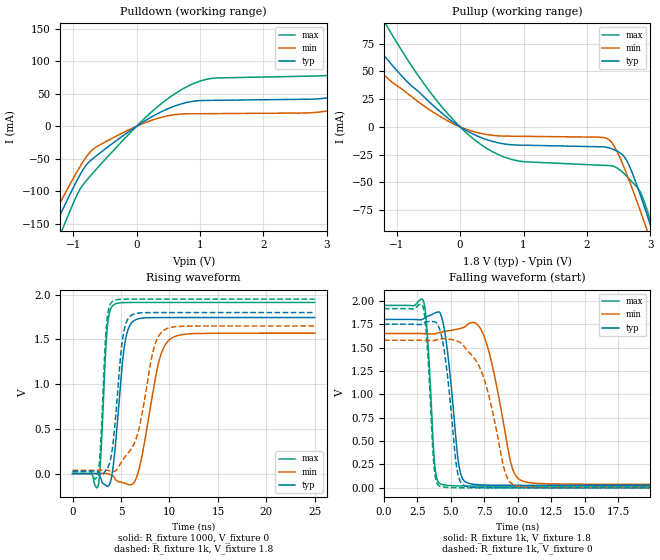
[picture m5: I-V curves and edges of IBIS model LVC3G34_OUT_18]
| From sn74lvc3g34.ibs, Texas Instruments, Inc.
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[Model]   LVC3G34_OUT_18
Model_type  Output
Vref =   0
Rref =   1000
Cref =   30p
Vmeas =   0.9
| variable   typ   min   max
C_comp   9.94pF   6.40pF   16.19pF
| C_pullup   9.16pF   6.40pF   10.36pF
| C_pulldown   10.71pF   6.76pF   16.19pF
[Temperature Range]   40   100   -40
| Ambient temperature   25   85   -40
[Voltage range]   1.8   1.65   1.95
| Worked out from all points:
|   slope of the pulldown table from 0 to 0.27 V, typ, clamps not added: 16.6 ohm
|   slope of the pullup table from 0 to 0.27 V, typ, clamps not added: 33.1 ohm
|   rising waveform, R_fixture 1000, V_fixture 0: 20-80 % time 867ps typ, 1.55ns min, 503ps max; typ from 0 V to 1.74 V
|   falling waveform, R_fixture 1k, V_fixture 1.8: 20-80 % time 716ps typ, 1.28ns min, 430ps max; typ from 1.8 V to 0.027 V
|   rising waveform, R_fixture 1k, V_fixture 1.8: 20-80 % time 873ps typ, 1.77ns min, 503ps max; typ from 0.027 V to 1.8 V
|   falling waveform, R_fixture 1k, V_fixture 0: 20-80 % time 748ps typ, 1.58ns min, 434ps max; typ from 1.75 V to 0 V
[Pulldown]
| LVC3G34_OUT_18
|   Voltage   I(typ)   I(min)   I(max)
-5V       -921.3mA   -834.5mA   -1.063A
-1.445V   -186.3mA   -162.4mA   -225.4mA
-1.25V    -145.7mA   -126mA     -178.1mA
-685mV    -49.64mA   -35.35mA   -71.84mA
610mV     31.45mA    17.97mA    50.48mA
1.215V    39.94mA    19.45mA    74.07mA
3.215V    47.58mA    27.04mA    81.89mA
3.75V     64.33mA    35.96mA    102.6mA
4.19V     79.14mA    21.53mA    128.3mA
4.615V    44.44mA    21.76mA    152.7mA
5.01V     44.71mA    21.99mA    83.17mA
10V       49.72mA    24.78mA    91.33mA
[Pullup]
| LVC3G34_OUT_18
|   Voltage   I(typ)   I(min)   I(max)
-5V       401.9mA    301.7mA    569.7mA
-1.995V   124.3mA    92.87mA    180.5mA
-1.525V   87.6mA     64.51mA    128.6mA
-1.245V   67.41mA    49.06mA    99.76mA
-215mV    8.959mA    6.079mA    13.21mA
460mV     -12.21mA   -7.201mA   -20.69mA
1.005V    -16.45mA   -8.461mA   -31.35mA
2.32V     -18.45mA   -10.52mA   -34.74mA
2.62V     -29.72mA   -41.55mA   -44.14mA
2.935V    -77.24mA   -91.1mA    -72.7mA
3.07V     -101mA     -113.7mA   -97.52mA
10V       -1.501A    -1.413A    -1.659A
[Ramp]
| LVC3G34_OUT_18
| variable   typ   min   max
dV/dt_r   1.13/9.33E-10   1.02/1.66E-09   1.24/5.46E-10
dV/dt_f   1.11/7.61E-10   1.04/1.41E-09   1.20/4.54E-10
R_load = 1k
[Rising Waveform]
| LVC3G34_OUT_18
R_fixture =   1000
C_fixture =   0
L_fixture =   0
V_fixture =   0
V_fixture_min = 0
V_fixture_max = 0
|   Time   V(typ)   V(min)   V(max)
0s        112.7pV    7.745nV    2.81nV
2.645ns   -9.907mV   1.897mV    -132.8mV
2.915ns   -53.04mV   2.167mV    194.2mV
3.555ns   -140.9mV   796.2uV    1.594V
4.24ns    126.2mV    -31.5mV    1.887V
5.33ns    1.408V     -105.5mV   1.912V
6.305ns   1.707V     -103.2mV   1.913V
8.89ns    1.744V     1.246V     1.913V
10.04ns   1.744V     1.5V       1.913V
24.99ns   1.744V     1.569V     1.913V
[Falling Waveform]
| LVC3G34_OUT_18
R_fixture =   1k
C_fixture =   0
L_fixture =   0
V_fixture =   1.8
V_fixture_min = 1.65
V_fixture_max = 1.95
|   Time   V(typ)   V(min)   V(max)
0s        1.8V       1.65V      1.95V
2.955ns   1.808V     1.648V     1.994V
3.27ns    1.834V     1.646V     1.58V
3.785ns   1.867V     1.647V     257.1mV
4.21ns    1.865V     1.663V     43.09mV
5.58ns    258.3mV    1.699V     20.91mV
6.11ns    61.74mV    1.728V     20.08mV
7.55ns    30.64mV    1.594V     19.58mV
10.17ns   27.23mV    85.41mV    19.52mV
24.99ns   26.98mV    37.55mV    19.51mV
[Rising Waveform]
| LVC3G34_OUT_18
R_fixture =   1k
C_fixture =   0
L_fixture =   0
V_fixture =   1.8
V_fixture_min = 1.65
V_fixture_max = 1.95
|   Time   V(typ)   V(min)   V(max)
0s        26.95mV    37.49mV    19.5mV
2.61ns    20.81mV    39.22mV    -6.802mV
2.89ns    -5.084mV   39.46mV    321.7mV
3.49ns    46.09mV    38.45mV    1.643V
4.125ns   295.4mV    24.99mV    1.925V
5.155ns   1.497V     147.9mV    1.949V
6.06ns    1.77V      275.6mV    1.95V
8.385ns   1.8V       1.398V     1.95V
9.44ns    1.8V       1.605V     1.95V
24.99ns   1.8V       1.65V      1.95V
[Falling Waveform]
| LVC3G34_OUT_18
R_fixture =   1k
C_fixture =   0
L_fixture =   0
V_fixture =   0
V_fixture_min = 0
V_fixture_max = 0
|   Time   V(typ)   V(min)   V(max)
0s        1.749V     1.578V     1.916V
2.93ns    1.755V     1.577V     1.928V
3.235ns   1.775V     1.575V     1.509V
3.725ns   1.776V     1.576V     251mV
4.125ns   1.71V      1.588V     21.38mV
5.435ns   217.2mV    1.571V     1.151mV
5.94ns    28.2mV     1.522V     468.6uV
7.385ns   2.007mV    1.205V     59.52uV
9.665ns   177.7uV    33.55mV    19.63uV
24.99ns   22.36uV    45.44uV    12.8uV
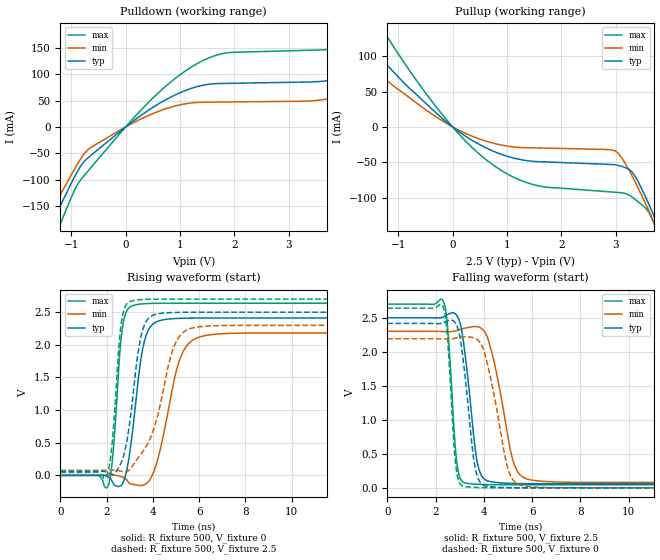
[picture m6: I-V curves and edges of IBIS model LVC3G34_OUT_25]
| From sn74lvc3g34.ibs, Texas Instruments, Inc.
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[Model]   LVC3G34_OUT_25
Model_type  Output
Vref =   0
Rref =   500
Cref =   30p
Vmeas =   1.25
| variable   typ   min   max
C_comp   9.77pF   6.16pF   14.04pF
| C_pullup   9.65pF   6.16pF   11.32pF
| C_pulldown   9.89pF   6.53pF   14.04pF
[Temperature Range]   40   100   -40
| Ambient temperature   25   85   -40
[Voltage range]   2.5   2.3   2.7
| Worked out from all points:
|   slope of the pulldown table from 0 to 0.375 V, typ, clamps not added: 13.1 ohm
|   slope of the pullup table from 0 to 0.375 V, typ, clamps not added: 19.1 ohm
|   rising waveform, R_fixture 500, V_fixture 0: 20-80 % time 503ps typ, 789ps min, 311ps max; typ from 0 V to 2.41 V
|   falling waveform, R_fixture 500, V_fixture 2.5: 20-80 % time 445ps typ, 700ps min, 284ps max; typ from 2.5 V to 0.06 V
|   rising waveform, R_fixture 500, V_fixture 2.5: 20-80 % time 533ps typ, 974ps min, 322ps max; typ from 0.06 V to 2.5 V
|   falling waveform, R_fixture 500, V_fixture 0: 20-80 % time 431ps typ, 694ps min, 272ps max; typ from 2.42 V to 0 V
[Pulldown]
| LVC3G34_OUT_25
|   Voltage   I(typ)   I(min)   I(max)
-5V       -962mA     -863.3mA   -1.124A
-1.53V    -221.1mA   -192.5mA   -267.7mA
-1.155V   -139.5mA   -119.8mA   -172mA
-665mV    -56.23mA   -40.89mA   -80.16mA
525mV     38.75mA    26.4mA     57.3mA
1.435V    79.4mA     46.8mA     126.7mA
3.83V     89.86mA    55.4mA     148.1mA
5.34V     157.5mA    105.8mA    231.8mA
5.91V     188.7mA    52.62mA    283.1mA
6.525V    93.57mA    53.13mA    299.2mA
7.5V      94.02mA    54.05mA    161.3mA
10V       98.03mA    56.54mA    166.6mA
[Pullup]
| LVC3G34_OUT_25
|   Voltage   I(typ)   I(min)   I(max)
-5V       476.9mA    373.6mA    668.8mA
-2.355V   194.1mA    148.5mA    277.6mA
-1.77V    138.1mA    104.6mA    199.1mA
-1.305V   96.51mA    72.23mA    140.3mA
-155mV    9.734mA    7.01mA     14.36mA
765mV     -34.86mA   -23.35mA   -54.93mA
1.6V      -49.31mA   -29.85mA   -83.81mA
2.995V    -53.63mA   -34.3mA    -92.61mA
3.335V    -67.41mA   -74.46mA   -101.3mA
3.72V     -128.9mA   -137.4mA   -139.3mA
3.8V      -143.3mA   -151.1mA   -154.4mA
10V       -1.404A    -1.319A    -1.567A
[Ramp]
| LVC3G34_OUT_25
| variable   typ   min   max
dV/dt_r   1.55/5.42E-10   1.40/8.48E-10   1.70/3.39E-10
dV/dt_f   1.51/4.63E-10   1.38/7.32E-10   1.64/2.95E-10
R_load = 500
[Rising Waveform]
| LVC3G34_OUT_25
R_fixture =   500
C_fixture =   0
L_fixture =   0
V_fixture =   0
V_fixture_min = 0
V_fixture_max = 0
|   Time   V(typ)   V(min)   V(max)
0s        123.5pV    5.828nV    2.514nV
2.065ns   -24.28mV   3.069mV    -156.4mV
2.265ns   -109mV     4.128mV    307.7mV
2.68ns    -128.5mV   -25.96mV   2.26V
3.18ns    866.4mV    -139.7mV   2.606V
3.515ns   1.859V     -153.7mV   2.627V
3.865ns   2.263V     -66.06mV   2.634V
5.155ns   2.406V     1.773V     2.637V
6.06ns    2.41V      2.126V     2.637V
24.99ns   2.411V     2.183V     2.637V
[Falling Waveform]
| LVC3G34_OUT_25
R_fixture =   500
C_fixture =   0
L_fixture =   0
V_fixture =   2.5
V_fixture_min = 2.3
V_fixture_max = 2.7
|   Time   V(typ)   V(min)   V(max)
0s        2.5V       2.3V       2.7V
2.32ns    2.511V     2.297V     2.745V
2.5ns     2.547V     2.295V     2.358V
2.875ns   2.536V     2.313V     383.8mV
3.21ns    1.996V     2.346V     73.62mV
3.88ns    193.9mV    2.348V     50.49mV
4.375ns   85.25mV    1.927V     46.75mV
5.22ns    65.14mV    387mV      45.35mV
5.81ns    61.99mV    127.9mV    45.17mV
24.99ns   60.11mV    78.17mV    45.05mV
[Rising Waveform]
| LVC3G34_OUT_25
R_fixture =   500
C_fixture =   0
L_fixture =   0
V_fixture =   2.5
V_fixture_min = 2.3
V_fixture_max = 2.7
|   Time   V(typ)   V(min)   V(max)
0s        60.06mV    78.1mV     45.02mV
2.015ns   48.04mV    80.46mV    17.05mV
2.235ns   13.22mV    82mV       497.6mV
2.63ns    198.6mV    64.23mV    2.328V
3.08ns    1.048V     126.6mV    2.671V
3.4ns     1.98V      289.5mV    2.69V
3.715ns   2.362V     450.8mV    2.696V
4.9ns     2.495V     1.963V     2.7V
5.675ns   2.499V     2.256V     2.7V
24.99ns   2.5V       2.3V       2.7V
[Falling Waveform]
| LVC3G34_OUT_25
R_fixture =   500
C_fixture =   0
L_fixture =   0
V_fixture =   0
V_fixture_min = 0
V_fixture_max = 0
|   Time   V(typ)   V(min)   V(max)
0s        2.416V     2.191V     2.64V
2.305ns   2.425V     2.189V     2.666V
2.485ns   2.453V     2.188V     2.238V
2.825ns   2.42V      2.2V       370.5mV
3.125ns   1.932V     2.221V     26.14mV
3.55ns    498.5mV    2.207V     8.694mV
3.78ns    123.1mV    2.161V     4.812mV
4.99ns    3.939mV    292.1mV    357.6uV
5.555ns   1.423mV    35.08mV    162.6uV
24.99ns   41.38uV    58.61uV    31.07uV
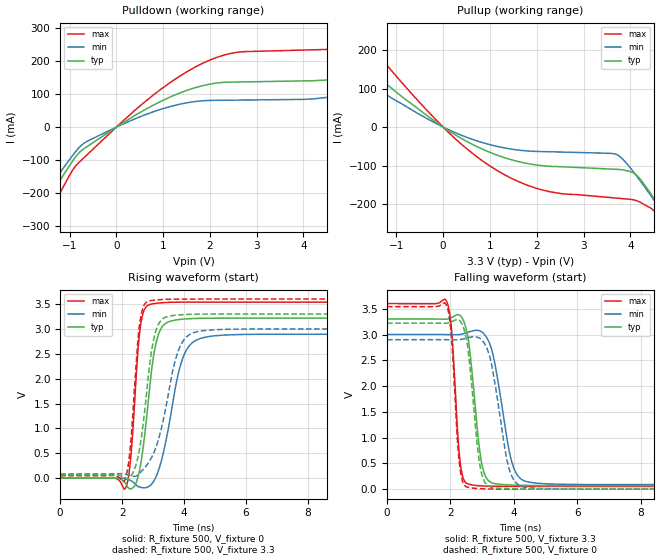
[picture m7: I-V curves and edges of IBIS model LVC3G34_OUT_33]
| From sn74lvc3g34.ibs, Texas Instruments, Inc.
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[Model]   LVC3G34_OUT_33
Model_type  Output
Vref =   0
Rref =   500
Cref =   50p
Vmeas =   1.5
| variable   typ   min   max
C_comp   9.49pF   5.86pF   12.60pF
| C_pullup   9.85pF   5.86pF   11.98pF
| C_pulldown   9.13pF   6.35pF   12.60pF
[Temperature Range]   40   100   -40
| Ambient temperature   25   85   -40
[Voltage range]   3.3   3   3.6
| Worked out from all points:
|   slope of the pulldown table from 0 to 0.495 V, typ, clamps not added: 11.3 ohm
|   slope of the pullup table from 0 to 0.495 V, typ, clamps not added: 13.6 ohm
|   rising waveform, R_fixture 500, V_fixture 0: 20-80 % time 365ps typ, 550ps min, 232ps max; typ from 0 V to 3.22 V
|   falling waveform, R_fixture 500, V_fixture 3.3: 20-80 % time 314ps typ, 471ps min, 208ps max; typ from 3.3 V to 0.069 V
|   rising waveform, R_fixture 500, V_fixture 3.3: 20-80 % time 381ps typ, 621ps min, 244ps max; typ from 0.069 V to 3.3 V
|   falling waveform, R_fixture 500, V_fixture 0: 20-80 % time 305ps typ, 452ps min, 203ps max; typ from 3.22 V to 0 V
[Pulldown]
| LVC3G34_OUT_33
|   Voltage   I(typ)   I(min)   I(max)
-5V       -1.007A    -894.5mA   -1.188A
-2.44V    -443.8mA   -389mA     -531.5mA
-1.495V   -228mA     -197.1mA   -278.2mA
-570mV    -53.91mA   -39.16mA   -76.55mA
975mV     79.99mA    55.23mA    117.5mA
2.315V    136.3mA    81.67mA    219.5mA
4.95V     154.8mA    103mA      243.8mA
6.98V     278.7mA    201.5mA    397.1mA
7.35V     308.5mA    129.4mA    437.7mA
7.84V     330.1mA    92.49mA    494.9mA
8.635V    176.4mA    93.08mA    532.7mA
10V       158.4mA    95.01mA    294.8mA
[Pullup]
| LVC3G34_OUT_33
|   Voltage   I(typ)   I(min)   I(max)
-5V       547.6mA    429.5mA    769.3mA
-3.23V    334.2mA    258.6mA    474.2mA
-2.495V   249.6mA    191.6mA    356.4mA
-1.985V   193mA      147.1mA    277.1mA
-95mV     7.957mA    5.812mA    11.78mA
1.095V    -70.05mA   -48.34mA   -108.1mA
2.165V    -100.6mA   -63.48mA   -164.5mA
3.71V     -109.5mA   -71.26mA   -184.2mA
4.145V    -126.1mA   -128.6mA   -191.4mA
4.775V    -234.9mA   -237.1mA   -267.2mA
5.015V    -281mA     -280.3mA   -317.6mA
10V       -1.311A    -1.23A     -1.479A
[Ramp]
| LVC3G34_OUT_33
| variable   typ   min   max
dV/dt_r   2.06/3.91E-10   1.85/5.94E-10   2.25/2.50E-10
dV/dt_f   1.99/3.29E-10   1.80/4.93E-10   2.18/2.23E-10
R_load = 500
[Rising Waveform]
| LVC3G34_OUT_33
R_fixture =   500
C_fixture =   0
L_fixture =   0
V_fixture =   0
V_fixture_min = 0
V_fixture_max = 0
|   Time   V(typ)   V(min)   V(max)
0s        141.8pV    5.06nV     2.398nV
2.11ns    -99.72mV   -10.64mV   -196.4mV
2.28ns    -212.4mV   -47.7mV    429.5mV
2.59ns    250.5mV    -181mV     3.045V
2.915ns   1.964V     -141.5mV   3.496V
3.095ns   2.715V     28.51mV    3.514V
3.315ns   3.062V     468.4mV    3.527V
3.95ns    3.196V     2.399V     3.538V
4.665ns   3.214V     2.832V     3.539V
24.99ns   3.216V     2.894V     3.539V
[Falling Waveform]
| LVC3G34_OUT_33
R_fixture =   500
C_fixture =   0
L_fixture =   0
V_fixture =   3.3
V_fixture_min = 3
V_fixture_max = 3.6
|   Time   V(typ)   V(min)   V(max)
0s        3.3V       3V         3.6V
1.89ns    3.3V       2.999V     3.628V
2.035ns   3.329V     2.997V     3.088V
2.315ns   3.364V     3.002V     477.3mV
2.63ns    2.572V     3.059V     89mV
2.91ns    807.3mV    3.074V     66.29mV
3.1ns     253.6mV    2.98V      60.57mV
3.94ns    79.83mV    516.4mV    54.03mV
4.47ns    72.62mV    136.2mV    53.48mV
24.99ns   69.39mV    87.32mV    53.2mV
[Rising Waveform]
| LVC3G34_OUT_33
R_fixture =   500
C_fixture =   0
L_fixture =   0
V_fixture =   3.3
V_fixture_min = 3
V_fixture_max = 3.6
|   Time   V(typ)   V(min)   V(max)
0s        69.35mV    87.26mV    53.17mV
2.08ns    11.9mV     82.03mV    -47.41mV
2.26ns    24.45mV    56.56mV    595mV
2.57ns    614.3mV    104.7mV    3.121V
2.7ns     1.198V     189.8mV    3.469V
2.9ns     2.335V     360mV      3.566V
3.2ns     3.125V     837.6mV    3.586V
3.82ns    3.281V     2.568V     3.599V
4.47ns    3.297V     2.951V     3.6V
24.99ns   3.3V       3V         3.6V
[Falling Waveform]
| LVC3G34_OUT_33
R_fixture =   500
C_fixture =   0
L_fixture =   0
V_fixture =   0
V_fixture_min = 0
V_fixture_max = 0
|   Time   V(typ)   V(min)   V(max)
0s        3.22V      2.9V       3.542V
1.875ns   3.219V     2.9V       3.564V
2.025ns   3.244V     2.898V     3.008V
2.295ns   3.266V     2.901V     430.2mV
2.575ns   2.6V       2.942V     34.26mV
2.86ns    762.2mV    2.946V     12.04mV
3.055ns   171.6mV    2.843V     6.59mV
3.84ns    8.734mV    418mV      878.9uV
4.32ns    2.894mV    40.73mV    332.7uV
24.99ns   36.21uV    46.68uV    28.99uV
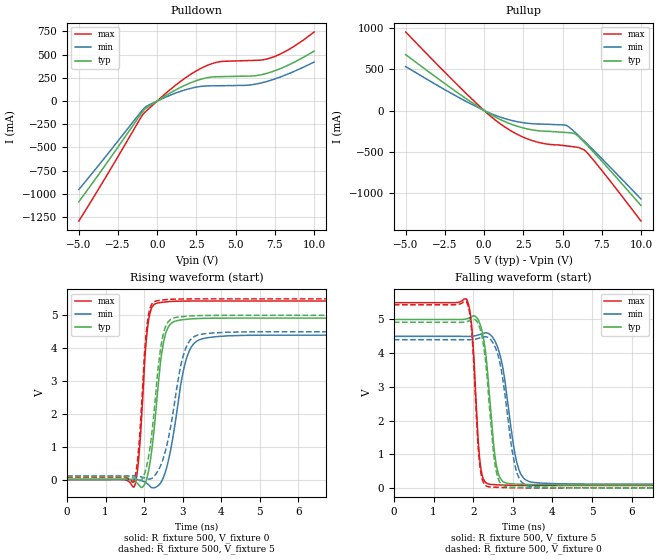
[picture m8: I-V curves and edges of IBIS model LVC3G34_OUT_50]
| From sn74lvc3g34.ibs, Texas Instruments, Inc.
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[Model]   LVC3G34_OUT_50
Model_type  Output
Vref =   0
Rref =   500
Cref =   50p
Vmeas =   2.5
| variable   typ   min   max
C_comp   8.93pF   5.46pF   12.38pF
| C_pullup   9.70pF   5.46pF   12.38pF
| C_pulldown   8.15pF   6.08pF   10.96pF
[Temperature Range]   40   100   -40
| Ambient temperature   25   85   -40
[Voltage range]   5   4.5   5.5
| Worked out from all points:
|   slope of the pulldown table from 0 to 0.75 V, typ, clamps not added: 9.57 ohm
|   slope of the pullup table from 0 to 0.75 V, typ, clamps not added: 9.17 ohm
|   rising waveform, R_fixture 500, V_fixture 0: 20-80 % time 260ps typ, 376ps min, 175ps max; typ from 0 V to 4.91 V
|   falling waveform, R_fixture 500, V_fixture 5: 20-80 % time 223ps typ, 318ps min, 154ps max; typ from 5 V to 0.09 V
|   rising waveform, R_fixture 500, V_fixture 5: 20-80 % time 268ps typ, 402ps min, 177ps max; typ from 0.09 V to 5 V
|   falling waveform, R_fixture 500, V_fixture 0: 20-80 % time 224ps typ, 312ps min, 153ps max; typ from 4.92 V to 0 V
[Pulldown]
| LVC3G34_OUT_50
|   Voltage   I(typ)   I(min)   I(max)
-5V       -1.085A    -953mA     -1.293A
-925mV    -115.1mA   -95.62mA   -147.4mA
-625mV    -68.8mA    -50.72mA   -96.83mA
1.06V     108.1mA    77.61mA    154.7mA
2.425V    214.3mA    146.7mA    317.2mA
3.59V     259.5mA    163mA      407.1mA
4.175V    262.2mA    164.4mA    426.1mA
5.89V     268.1mA    171.9mA    435.3mA
6.74V     286.3mA    198.6mA    443mA
7.465V    323mA      234.9mA    477.5mA
8.625V    408mA      310.8mA    578.1mA
10V       536.4mA    418mA      742.1mA
[Pullup]
| LVC3G34_OUT_50
|   Voltage   I(typ)   I(min)   I(max)
-5V       673.9mA    530.1mA    946.1mA
-985mV    122.4mA    93.65mA    175.9mA
240mV     -27.95mA   -20.84mA   -40.82mA
1.115V    -115.9mA   -84.71mA   -171.7mA
2.1V      -188.7mA   -134mA     -285.4mA
3.08V     -233.7mA   -159.1mA   -363.2mA
3.96V     -250.6mA   -165.4mA   -403mA
5.285V    -265.7mA   -183.8mA   -427.4mA
5.82V     -284mA     -266.4mA   -439.7mA
6.485V    -402.3mA   -386.4mA   -491.6mA
7.725V    -656.8mA   -621.8mA   -774mA
10V       -1.144A    -1.066A    -1.332A
[Ramp]
| LVC3G34_OUT_50
| variable   typ   min   max
dV/dt_r   3.10/2.81E-10   2.79/4.05E-10   3.40/1.89E-10
dV/dt_f   3.01/2.30E-10   2.70/3.35E-10   3.33/1.62E-10
R_load = 500
[Rising Waveform]
| LVC3G34_OUT_50
R_fixture =   500
C_fixture =   0
L_fixture =   0
V_fixture =   0
V_fixture_min = 0
V_fixture_max = 0
|   Time   V(typ)   V(min)   V(max)
0s        181.8pV    4.332nV    2.343nV
1.75ns    -55.41mV   4.428mV    -202.2mV
1.87ns    -172.8mV   -16.24mV   764mV
2.1ns     171.6mV    -142mV     4.704V
2.345ns   2.603V     -206.7mV   5.372V
2.48ns    4.01V      6.602mV    5.396V
2.65ns    4.679V     673.8mV    5.417V
3.105ns   4.879V     3.699V     5.433V
3.61ns    4.908V     4.31V      5.435V
24.99ns   4.914V     4.397V     5.435V
[Falling Waveform]
| LVC3G34_OUT_50
R_fixture =   500
C_fixture =   0
L_fixture =   0
V_fixture =   5
V_fixture_min = 4.5
V_fixture_max = 5.5
|   Time   V(typ)   V(min)   V(max)
0s        5V         4.5V       5.5V
1.845ns   5.023V     4.497V     5.574V
1.975ns   5.089V     4.502V     4.62V
2.18ns    4.836V     4.561V     691.4mV
2.415ns   2.687V     4.565V     107.6mV
2.545ns   983.5mV    4.368V     94.37mV
2.67ns    313.1mV    3.975V     85.91mV
3.105ns   111.8mV    734.5mV    73.64mV
3.5ns     97.35mV    163.5mV    71.27mV
24.99ns   89.64mV    109.7mV    70.16mV
[Rising Waveform]
| LVC3G34_OUT_50
R_fixture =   500
C_fixture =   0
L_fixture =   0
V_fixture =   5
V_fixture_min = 4.5
V_fixture_max = 5.5
|   Time   V(typ)   V(min)   V(max)
0s        89.62mV    109.7mV    70.15mV
1.73ns    52.6mV     115.3mV    -60.91mV
1.855ns   -21.82mV   99.23mV    889.8mV
2.09ns    529.5mV    21.25mV    4.82V
2.345ns   3.166V     234.4mV    5.444V
2.47ns    4.272V     543.6mV    5.464V
2.615ns   4.782V     1.164V     5.481V
3.03ns    4.965V     3.819V     5.497V
3.5ns     4.993V     4.426V     5.5V
24.99ns   5V         4.5V       5.5V
[Falling Waveform]
| LVC3G34_OUT_50
R_fixture =   500
C_fixture =   0
L_fixture =   0
V_fixture =   0
V_fixture_min = 0
V_fixture_max = 0
|   Time   V(typ)   V(min)   V(max)
0s        4.917V     4.401V     5.437V
1.84ns    4.937V     4.398V     5.501V
1.965ns   4.992V     4.402V     4.593V
2.17ns    4.737V     4.452V     644.1mV
2.4ns     2.546V     4.448V     28.52mV
2.535ns   831.4mV    4.227V     19.49mV
2.655ns   206.4mV    3.815V     13.86mV
3.06ns    17.77mV    637.3mV    3.475mV
3.42ns    7.4mV      49.16mV    1.239mV
24.99ns   15.85uV    21.8uV     13.79uV
